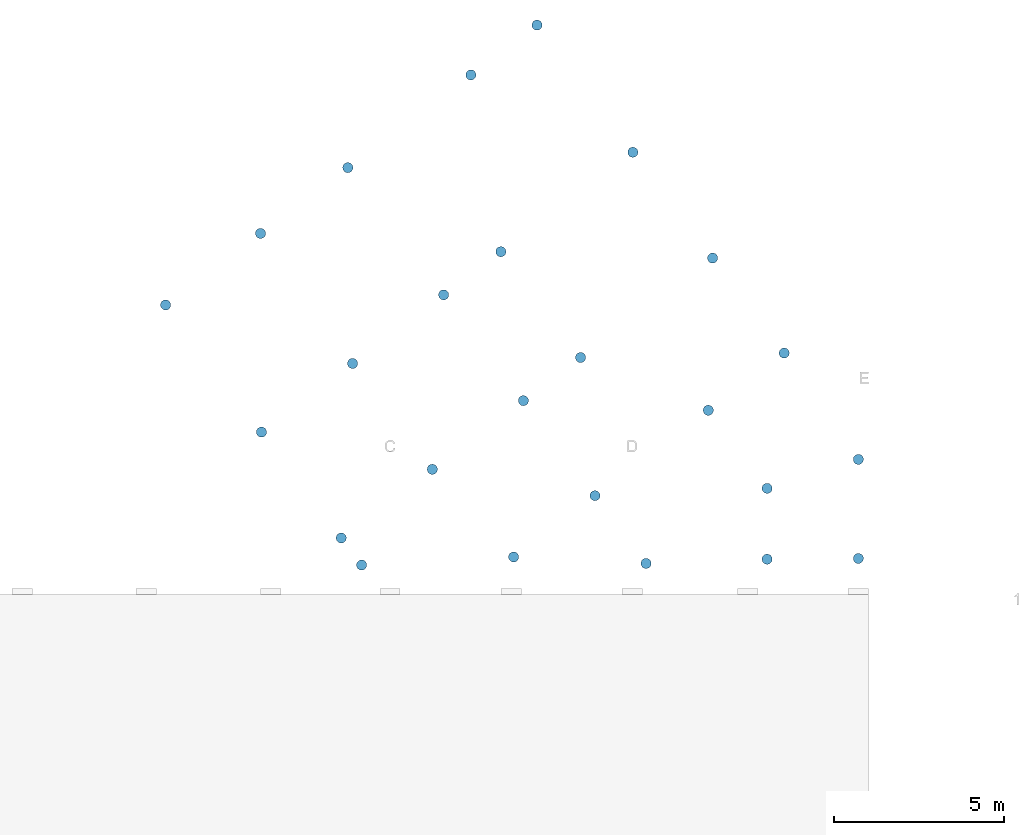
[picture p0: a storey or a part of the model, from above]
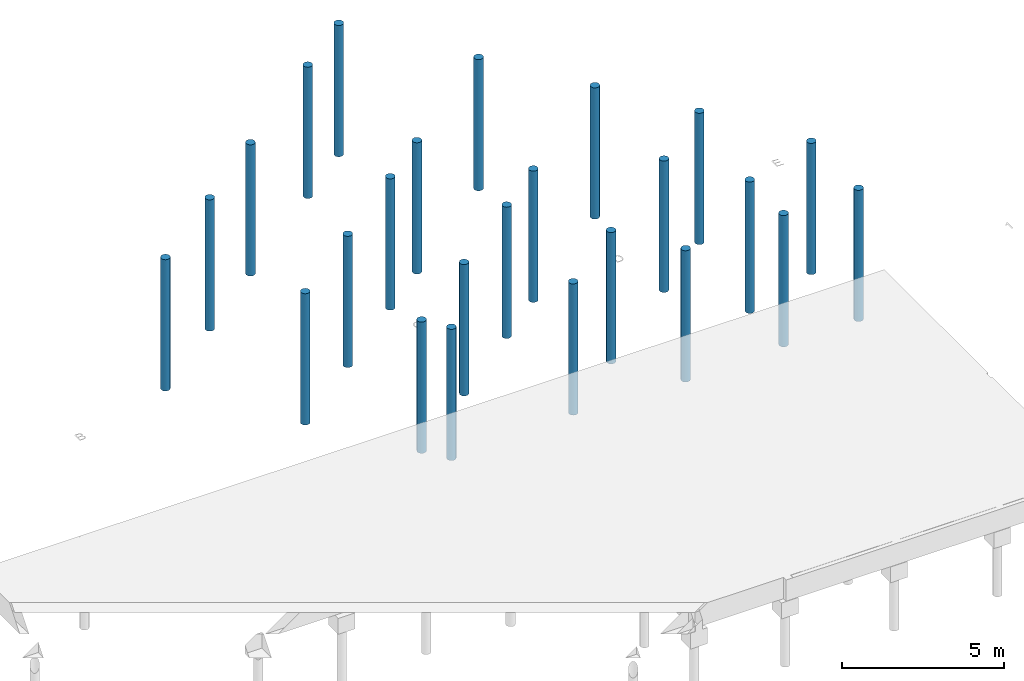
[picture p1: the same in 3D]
Properties of the parts of a building model (IFC2X3)

# File
Description: ViewDefinition [CoordinationView_V2.0], Option [Drawing Scale: 100.000000], Option [Global Unique Identifiers (GUID): Keep existing], Option [Elements to export: Entire project], Option [Partial Structure Display: Entire Model], Option [IFC Domain: All], Option [Structural Function: All Elements], Option [Convert Grid elements: On], Option [Convert IFC Annotations and ArchiCAD 2D elements: On], Option [Convert 2D symbols of Doors and Windows: Off], Option [Explode Composite and Complex Profile elements into parts: Off], Option [Export geometries that Participates in Collision Detection only: Off], Option [Multi-skin complex geometries: Building element parts], Option [Elements in Solid Element Operations: Extruded/revolved], Option [Elements with junctions: Extruded/revolved without junctions], Option [Slabs with slanted edge(s): Extruded], Option [Use legacy geometric methods as in Coordination View 1.0: Off], Option [IFC Site Geometry: As boundary representation (BRep)], Option [Properties To Export: All properties], Option [Space containment: Off], Option [Bounding Box: Off], Option [Geometry to type objects: Off], Option [IFC base quantities (size, area and volume): Off], Option [All ArchiCAD BIM parameters: On], Option [IFC Space boundaries: Off], Option [ArchiCAD Zone Categories as IFC Space classification data: Off]
File name: J:\STATION DOCUMENTS\TB2E COMMI\SESSION 2016\Agonac PLN\test IFC\maquette01.ifc
Time: 2016-01-28T13:49:23
Author: Architect
Organization: Building Designer Office
Written by: PreProc - EDM 5.0
Made in: IFC file generated by Graphisoft ArchiCAD-64 19.0.0 FRA FULL Windows version (IFC2x3 add-on version: 3003 FRA FULL).
Authorization: The authorising person

# IfcProject, Default Project
Description: Description of Default Project

# IfcSite, Default Site
Description: Description of Default Site; RefLatitude: 24, 28, 0, 0; RefLongitude: 54, 25, 0, 0; RefElevation: 10 mm

# IfcBuilding, Default Building
Description: Description of Default Building

# IfcBuildingStorey (4)
In: Default Building
Name | Elevation (mm)
FONDATIONS PROFONDES | -3600
FONDATIONS SUPERFICIELLES | -1600
RDC MAIRE | 0
REZ JARDIN LOISIRS | 3950

# IfcBeam: Longrine becquet 200 x 800 (18)
In: FONDATIONS SUPERFICIELLES
Material: Struct. - B.A. coulé
BE BETON - Enrobage: 3 cm; Type béton: XC1; Ratio Acier: 150 kg/m3; Classe béton: C25/30
ArchiCADProperties - Etage d'implantation: FONDATIONS SUPERFICIELLES; Calque: Longrine becquet 20x80 ht; Type: Poutre; Verrouillé: no; Matériau de construction / Composite / Profil / Hachure: Longrine becquet; Fonction structurelle: Elément porteur; Position: Extérieur; Classification d'élement: Poutre; Etat de rénovation: Existant; Afficher sur filtre de rénovation: Tous les filtres appropriés; Type de structure: Profil complexe; Matériau de construction / Profil: Longrine becquet; Angle d'inclinaison de poutre: 0 deg; Coupe transversale de poutre: Profilé
AC_Pset_RenovationAndPhasing - Renovation Status: Existing
Pset_BeamCommon - LoadBearing: yes; IsExternal: yes; Reference: Longrine becquet 200 x 800
ArchiCADQuantities - Altitude à Zéro du Projet: 2950 mm; Altitude à étage: 4550 mm; Hauteur: 800 mm; Surface de fin: 0.245 m2; Surface des trous: 0 m2; Surface des arêtes de trou: 0 m2; Nombre de trous: 0; Volume des trous: 0 m3; Largeur des trous: 0 mm; Hauteur du trou: 0 mm; Niveau du trou: 0 mm; Largeur: 200 mm; Décalage: 0 mm
Name | ID Elément entier = ID Elément compact | Superficie de surface (m2) | Volume net (m3) = Volume (m3) = Volume conditionnel (m3) | Superficie (m2) = Surface inférieure (m2) = Surface supérieure (m2) | Longueur droite (mm) = Longueur gauche (mm) | Surface côté gauche (m2) = Surface côté droit (m2)
LONGRINE_B_20x80-015 | LONGRINE_B_20x80-015 | 1.82354 | 0.0966857 | 0.157854 | 789.271 | 0.631417
LONGRINE_B_20x80-014 | LONGRINE_B_20x80-014 | 5.28219 | 0.308528 | 0.503719 | 2518.6 | 2.01488
LONGRINE_B_20x80-012 | LONGRINE_B_20x80-012 | 5.87681 | 0.344949 | 0.563181 | 2815.91 | 2.25273
LONGRINE_B_20x80-013 | LONGRINE_B_20x80-013 | 10.871 | 0.650843 | 1.0626 | 5313 | 4.2504
LONGRINE_B_20x80-016 | LONGRINE_B_20x80-016 | 1.845 | 0.098 | 0.16 | 800 | 0.64
LONGRINE_B_20x80-011 | LONGRINE_B_20x80-011 | 5.62033 | 0.329239 | 0.537533 | 2687.67 | 2.15013
LONGRINE_B_20x80-009 | LONGRINE_B_20x80-009 | 5.645 | 0.33075 | 0.54 | 2700 | 2.16
LONGRINE_B_20x80-010 | LONGRINE_B_20x80-010 | 1.73299 | 0.0911397 | 0.148799 | 743.997 | 0.595198
LONGRINE_B_20x80-008 | LONGRINE_B_20x80-008 | 7.61995 | 0.451716 | 0.737495 | 3687.48 | 2.94998
LONGRINE_B_20x80-007 | LONGRINE_B_20x80-007 | 6.855 | 0.404862 | 0.661 | 3305 | 2.644
LONGRINE_B_20x80-006 | LONGRINE_B_20x80-006 | 7.653 | 0.45374 | 0.7408 | 3704 | 2.9632
LONGRINE_B_20x80-005 | LONGRINE_B_20x80-005 | 9.227 | 0.550147 | 0.8982 | 4491 | 3.5928
LONGRINE_B_20x80-004 | LONGRINE_B_20x80-004 | 4.725 | 0.2744 | 0.448 | 2240 | 1.792
LONGRINE_B_20x80-003 | LONGRINE_B_20x80-003 | 8.925 | 0.53165 | 0.868 | 4340 | 3.472
LONGRINE_B_20x80-002 | LONGRINE_B_20x80-002 | 6.285 | 0.36995 | 0.604 | 3020 | 2.416
LONGRINE_B_20x80-017 | LONGRINE_B_20x80-017 | 7.653 | 0.45374 | 0.7408 | 3704 | 2.9632
LONGRINE_B_20x80-018 | LONGRINE_B_20x80-018 | 9.227 | 0.550147 | 0.8982 | 4491 | 3.5928
LONGRINE_B_20x80-001 | LONGRINE_B_20x80-001 | 6.845 | 0.40425 | 0.66 | 3300 | 2.64

# IfcBeam: Struct. - B.A. coulé 200 x 550 (20)
In: FONDATIONS SUPERFICIELLES
Material: Struct. - B.A. coulé
BE BETON - Enrobage: 3 cm; Type béton: XC1; Ratio Acier: 150 kg/m3
ArchiCADProperties - Etage d'implantation: FONDATIONS SUPERFICIELLES; Calque: Longrine 20x55 ht; Type: Poutre; Verrouillé: yes; Matériau de construction / Composite / Profil / Hachure: Struct. - B.A. coulé; Fonction structurelle: Elément porteur; Position: Extérieur; Classification d'élement: Poutre; Etat de rénovation: Existant; Afficher sur filtre de rénovation: Tous les filtres appropriés; Type de structure: Basique; Surface supérieure: Béton - Brut de décoffrage (Planches); Surface inférieure: Béton - Brut de décoffrage (Planches); Surface gauche: Béton - Brut de décoffrage (Planches); Surface droite: Béton - Brut de décoffrage (Planches); Surface de fin: Béton - Brut de décoffrage (Planches); Matériau de construction / Profil: Struct. - B.A. coulé; Angle d'inclinaison de poutre: 0 deg; Coupe transversale de poutre: Rectangulaire
AC_Pset_RenovationAndPhasing - Renovation Status: Existing
Pset_BeamCommon - LoadBearing: yes; IsExternal: yes; Reference: Struct. - B.A. coulé 200 x 550
ArchiCADQuantities - Altitude à Zéro du Projet: 3500 mm; Altitude à étage: 5100 mm; Hauteur: 550 mm; Surface de fin: 0.22 m2; Surface des trous: 0 m2; Surface des arêtes de trou: 0 m2; Nombre de trous: 0; Volume des trous: 0 m3; Largeur des trous: 0 mm; Hauteur du trou: 0 mm; Niveau du trou: 0 mm; Largeur: 200 mm; Décalage: 0 mm
Name | Classe béton | ID Elément entier = ID Elément compact | Superficie de surface (m2) | Volume net (m3) = Volume (m3) = Volume conditionnel (m3) | Superficie (m2) = Surface inférieure (m2) = Surface supérieure (m2) | Longueur droite (mm) = Longueur gauche (mm) | Surface côté gauche (m2) = Surface côté droit (m2)
LONGRINE_20x55-020 | C25/30 | LONGRINE_20x55-020 | 1.30318 | 0.079433 | 0.144424 | 722.118 | 0.397165
LONGRINE_20x55-019 | C25/30 | LONGRINE_20x55-019 | 3.15156 | 0.214981 | 0.390875 | 1954.37 | 1.07491
LONGRINE_20x55-017 | C25/30 | LONGRINE_20x55-017 | 4.2385 | 0.29469 | 0.5358 | 2679 | 1.47345
LONGRINE_20x55-015 | C25/30 | LONGRINE_20x55-015 | 4.12 | 0.286 | 0.52 | 2600 | 1.43
LONGRINE_20x55-014 | C25/30 | LONGRINE_20x55-014 | 6.19 | 0.4378 | 0.796 | 3980 | 2.189
LONGRINE_20x55-012 | C25/30 | LONGRINE_20x55-012 | 2.08473 | 0.136747 | 0.24863 | 1243.15 | 0.683733
LONGRINE_20x55-013 | C25/30 | LONGRINE_20x55-013 | 4.42 | 0.308 | 0.56 | 2800 | 1.54
LONGRINE_20x55-018 | C25/30 | LONGRINE_20x55-018 | 1.26617 | 0.0767188 | 0.139489 | 697.443 | 0.383594
LONGRINE_20x55-016 | C25/30 | LONGRINE_20x55-016 | 3.67 | 0.253 | 0.46 | 2300 | 1.265
LONGRINE-011 |  | LONGRINE-011 | 5.1775 | 0.36355 | 0.661 | 3305 | 1.81775
LONGRINE_20x55-006 | C25/30 | LONGRINE_20x55-006 | 5.776 | 0.40744 | 0.7408 | 3704 | 2.0372
LONGRINE_20x55-010 | C25/30 | LONGRINE_20x55-010 | 7.22734 | 0.513872 | 0.934312 | 4671.56 | 2.56936
LONGRINE_20x55-009 | C25/30 | LONGRINE_20x55-009 | 3.08266 | 0.209928 | 0.381688 | 1908.44 | 1.04964
LONGRINE_20x55-008 | C25/30 | LONGRINE_20x55-008 | 4.96 | 0.3476 | 0.632 | 3160 | 1.738
LONGRINE_20x55-007 | C25/30 | LONGRINE_20x55-007 | 4.96 | 0.3476 | 0.632 | 3160 | 1.738
LONGRINE_20x55-005 | C25/30 | LONGRINE_20x55-005 | 7.22734 | 0.513872 | 0.934312 | 4671.56 | 2.56936
LONGRINE_20x55-004 | C25/30 | LONGRINE_20x55-004 | 3.0865 | 0.21021 | 0.3822 | 1911 | 1.05105
LONGRINE_20x55-003 | C25/30 | LONGRINE_20x55-003 | 4.96 | 0.3476 | 0.632 | 3160 | 1.738
LONGRINE_20x55-002 | C25/30 | LONGRINE_20x55-002 | 4.96 | 0.3476 | 0.632 | 3160 | 1.738
LONGRINE_20x55-001 | C25/30 | LONGRINE_20x55-001 | 6.9565 | 0.49401 | 0.8982 | 4491 | 2.47005

# IfcFooting, Fondations mairie
In: FONDATIONS PROFONDES
Material: Sans Trame
ArchiCADProperties - ID Elément entier: Fondations mairie; ID Elément compact: Fondations mairie; Etage d'implantation: FONDATIONS PROFONDES; Calque: Fondations Mairie; Type: Objet; Verrouillé: no; Nom Elément de Bibliothèque: mairie; Matériau de construction / Composite / Profil / Hachure: Sans Trame; Fonction structurelle: Elément porteur; Position: Extérieur; Classification d'élement: Empattement; Etat de rénovation: Existant; Afficher sur filtre de rénovation: Tous les filtres appropriés; Angle de rotation: 0 deg; Surface: Peinture - Noir
AC_Pset_mairie - Afficher points chauds 2D en 3D: yes; Utiliser environnement mémorisé: no; Hachure 1: Béton armé; Hachure 2: Sans Trame; Hachure 3: Hachure solide; Ligne 1: 1; Ligne 2: 21; Ligne 3: 6; Ligne 4: 7; Surface 1: Béton - Brut de décoffrage (Planches); Surface 2: Peinture - Noir; Surface 3: Béton - Lissé; Surface 4: 0; Surface 5: Béton - Brut; Surface 6: Métal - Zinc; Surface 7: Peinture - Vermilion; Stylo 1: Fond - Couleur 1; Stylo 2: Général - Dessin; Stylo 3: Général - fonds de hachures; Stylo 4: Béton armé; Stylo 5: Poteaux - Contours; Stylo 6: Poteaux - fonds de hachure; Stylo 7: Poteaux - Hachures coupées; Stylo 8: Poteaux - Coupé structurel; Stylo 9: Objets - Général; Stylo 10: Eléments 2D - Général; Stylo 11: Système d'axe
AC_Pset_RenovationAndPhasing - Renovation Status: Existing
ArchiCADQuantities - Altitude à Zéro du Projet: -3600 mm; Altitude à étage: -4.44089e-13 mm; Superficie de surface: 1274.78 m2; Volume net: 126.644 m3; Superficie: 905.232 m2; Hauteur (Taille en Z): 3600 mm; Longueur (A): 40115 mm; Volume: 126.644 m3; Largeur (B): 22565.9 mm
AC_Equantity_mairie - 1ère dimension: 40115 mm; 2ème dimension: 22565.9 mm; Hauteur: 3600 mm; Niveau inférieur: 1000 mm; Niveau supérieur: 0 mm

# IfcFooting: Massifs (25)
In: FONDATIONS SUPERFICIELLES
Material: Struct. - B.A. coulé
BE BETON - Type de béton: XC1; Enrobage aciers: 3 cm; Ratio Acier: 80 kg/m3; Classe béton: C25/30
ArchiCADProperties - Etage d'implantation: FONDATIONS SUPERFICIELLES; Calque: Massifs loisir; Type: Poteau; Verrouillé: no; Matériau de construction / Composite / Profil / Hachure: Struct. - B.A. coulé; Fonction structurelle: Elément porteur; Position: Non défini; Classification d'élement: Empattement; Etat de rénovation: Existant; Afficher sur filtre de rénovation: Tous les filtres appropriés; Type de structure: Basique; Matériau de construction / Profil: Struct. - B.A. coulé; Surface: Béton - Brut de décoffrage (Planches); Angle d'inclinaison de poteau: 90 deg; Coupe transversale de poteau: Rectangulaire; Etage supérieur lié: Non lié
AC_Pset_RenovationAndPhasing - Renovation Status: Existing
ArchiCADQuantities - Altitude à Zéro du Projet: 2350 mm; Altitude à étage: 3950 mm; Hauteur: 600 mm; Superficie de surface: 1.44 m2; Volume net: 0.216 m3; Superficie: 0.36 m2; Surface nette de l'âme (sans haut/bas): 1.44 m2; Surface du revêtement: 0 m2; Volume net de l'Ame: 0.216 m3; Volume net du revêtement: 0 m3; Dimensions Ame: 600 mm; 2ème dimension âme: 600 mm; Hauteur minimum du Poteau: 600 mm; Hauteur maximum Poteau: 600 mm; Périmètre du Poteau: 2400 mm; Surface du Poteau: 0.36 m2; Volume du Poteau: 0.216 m3; Volume brut du Poteau: 0.216 m3; Surface brute de l'âme (sans haut/bas): 1.44 m2; Volume brut de l'Ame: 0.216 m3; Surface brute du revêtement (sans haut/bas): 0 m2; Volume brut du revêtement: 0 m3; Surface nette du haut de l'Ame: 0.36 m2; Surface nette du bas de l'Ame: 0.36 m2; Surface nette du haut du Revêtement: 0 m2; Surface nette du bas du Revêtement: 0 m2; Surface brute du haut (ou bas) de l'âme: 0.36 m2; Surface brute du haut (ou bas) du revêtement: 0 m2; Décalage étage d'implantation: 3950 mm; Décalage supérieur: -300 mm
Name | ID Elément entier = ID Elément compact
Plot-051 | Plot-051
Plot-060 | Plot-060
Plot-038 | Plot-038
Plot-036 | Plot-036
Plot-041 | Plot-041
Plot-039 | Plot-039
Plot-053 | Plot-053
Plot-050 | Plot-050
Plot-055 | Plot-055
Plot-056 | Plot-056
Plot-054 | Plot-054
Plot-059 | Plot-059
Plot-052 | Plot-052
Plot-057 | Plot-057
Plot-058 | Plot-058
Plot-043 | Plot-043
Plot-045 | Plot-045
Plot-037 | Plot-037
Plot-042 | Plot-042
Plot-044 | Plot-044
Plot-047 | Plot-047
Plot-048 | Plot-048
Plot-049 | Plot-049
Plot-046 | Plot-046
Plot-040 | Plot-040

# IfcPile (25)
In: FONDATIONS PROFONDES
Material: Struct. - B.A. coulé
ArchiCADProperties - Etage d'implantation: FONDATIONS PROFONDES; Calque: Pieu loisir; Type: Poteau; Verrouillé: no; Matériau de construction / Composite / Profil / Hachure: Struct. - B.A. coulé; Fonction structurelle: Elément porteur; Position: Extérieur; Classification d'élement: Pieu; Etat de rénovation: Existant; Afficher sur filtre de rénovation: Tous les filtres appropriés; Type de structure: Basique; Matériau de construction / Profil: Struct. - B.A. coulé; Surface: Béton - Brut de décoffrage (Planches); Angle d'inclinaison de poteau: 90 deg; Coupe transversale de poteau: Circulaire; Etage supérieur lié: Propre étage + 1 (1. FONDATIONS SUPERFICIELLES)
AC_Pset_RenovationAndPhasing - Renovation Status: Existing
ArchiCADQuantities - Altitude à Zéro du Projet: -2600 mm; Altitude à étage: 1000 mm; Hauteur: 4950 mm; Superficie de surface: 4.65548 m2; Volume net: 0.346966 m3; Superficie: 0.0706858 m2; Surface nette de l'âme (sans haut/bas): 4.65548 m2; Surface du revêtement: 0 m2; Volume net de l'Ame: 0.346966 m3; Volume net du revêtement: 0 m3; Dimensions Ame: 300 mm; 2ème dimension âme: 300 mm; Hauteur minimum du Poteau: 4950 mm; Hauteur maximum Poteau: 4950 mm; Périmètre du Poteau: 942.478 mm; Surface du Poteau: 0.0706858 m2; Volume du Poteau: 0.346966 m3; Volume brut du Poteau: 0.346966 m3; Surface brute de l'âme (sans haut/bas): 4.65548 m2; Volume brut de l'Ame: 0.346966 m3; Surface brute du revêtement (sans haut/bas): 0 m2; Volume brut du revêtement: 0 m3; Surface nette du haut de l'Ame: 0.0700941 m2; Surface nette du bas de l'Ame: 0.0700941 m2; Surface nette du haut du Revêtement: 0 m2; Surface nette du bas du Revêtement: 0 m2; Surface brute du haut (ou bas) de l'âme: 0.0706858 m2; Surface brute du haut (ou bas) du revêtement: 0 m2; Décalage étage d'implantation: 1000 mm; Décalage supérieur: 3950 mm
Name | ID Elément entier = ID Elément compact
Pieu-005 | Pieu-005
Pieu-004 | Pieu-004
Pieu-003 | Pieu-003
Pieu-002 | Pieu-002
Pieu001 | Pieu001
Pieu-006 | Pieu-006
Pieu-007 | Pieu-007
Pieu-008 | Pieu-008
Pieu-009 | Pieu-009
Pieu-010 | Pieu-010
Pieu-015 | Pieu-015
Pieu-014 | Pieu-014
Pieu-013 | Pieu-013
Pieu-012 | Pieu-012
Pieu-011 | Pieu-011
Pieu-016 | Pieu-016
Pieu-020 | Pieu-020
Pieu-019 | Pieu-019
Pieu-022 | Pieu-022
Pieu-023 | Pieu-023
Pieu-025 | Pieu-025
Pieu-024 | Pieu-024
Pieu-021 | Pieu-021
Pieu-018 | Pieu-018
Pieu-017 | Pieu-017

# IfcSlab: Struct. - B.A. coulé (30)
In: FONDATIONS SUPERFICIELLES
PredefinedType: FLOOR; Material: Struct. - B.A. coulé
ArchiCADProperties - Etage d'implantation: FONDATIONS SUPERFICIELLES; Calque: Clavetage; Type: Forme; Verrouillé: no; Matériau de construction / Composite / Profil / Hachure: Struct. - B.A. coulé; Fonction structurelle: Elément porteur; Classification d'élement: Dalle; Etat de rénovation: Existant; Afficher sur filtre de rénovation: Tous les filtres appropriés; Hachure: Struct. - B.A. coulé; Surface: Béton - Brut de décoffrage (Planches); Ombres portées: yes; Recevoir ombre: yes; Classification par DIN: Non défini
AC_Pset_RenovationAndPhasing - Renovation Status: Existing
Pset_SlabCommon - LoadBearing: yes
ArchiCADQuantities - Altitude à Zéro du Projet: 2950 mm; Altitude à étage: 4550 mm
Name | ID Elément entier = ID Elément compact | Position | Superficie de surface (m2) | Volume net (m3) = Volume (m3) | Superficie (m2) | Périmètre (mm) | IsExternal
Clav-024 | Clav-024 | Non défini | 0.420189 | 0.0146805 | 0.0266919 | 666.919
Clav-020 | Clav-020 | Extérieur | 0.52 | 0.022 | 0.04 | 800 | yes
Clav-021 | Clav-021 | Extérieur | 0.52 | 0.022 | 0.04 | 800 | yes
Clav-012 | Clav-012 | Extérieur | 0.52 | 0.022 | 0.04 | 800 | yes
Clav-013 | Clav-013 | Extérieur | 0.52 | 0.022 | 0.04 | 800 | yes
Clav-014 | Clav-014 | Extérieur | 0.52 | 0.022 | 0.04 | 800 | yes
Clav-009 | Clav-009 | Extérieur | 0.52 | 0.022 | 0.04 | 800 | yes
Clav-022 | Clav-022 | Extérieur | 0.52 | 0.022 | 0.04 | 800 | yes
Clav-015 | Clav-015 | Extérieur | 0.52 | 0.022 | 0.04 | 800 | yes
Clav-005 | Clav-005 | Extérieur | 0.52 | 0.022 | 0.04 | 800 | yes
Clav-004 | Clav-004 | Extérieur | 0.52 | 0.022 | 0.04 | 800 | yes
Clav-003 | Clav-003 | Extérieur | 0.52 | 0.022 | 0.04 | 800 | yes
Clav-002 | Clav-002 | Extérieur | 0.52 | 0.022 | 0.04 | 800 | yes
Clav-010 | Clav-010 | Extérieur | 0.52 | 0.022 | 0.04 | 800 | yes
Clav-008 | Clav-008 | Extérieur | 0.52 | 0.022 | 0.04 | 800 | yes
Clav-007 | Clav-007 | Extérieur | 0.52 | 0.022 | 0.04 | 800 | yes
Clav-016 | Clav-016 | Extérieur | 0.52 | 0.022 | 0.04 | 800 | yes
Clav-011 | Clav-011 | Extérieur | 0.52 | 0.022 | 0.04 | 800 | yes
Clav-006 | Clav-006 | Extérieur | 0.52 | 0.022 | 0.04 | 800 | yes
Clav-001 | Clav-001 | Extérieur | 0.52 | 0.022 | 0.04 | 800 | yes
Clav-030 | Clav-030 | Non défini | 0.52 | 0.022 | 0.04 | 800
Clav-026 | Clav-026 | Non défini | 0.680939 | 0.0358361 | 0.0651565 | 1001.14
Clav-028 | Clav-028 | Non défini | 0.499708 | 0.0205116 | 0.0372938 | 772.946
Clav-018 | Clav-018 | Non défini | 0.844768 | 0.0511536 | 0.0930065 | 1197.74
Clav-023 | Clav-023 | Non défini | 0.52 | 0.022 | 0.04 | 800
Clav-025 | Clav-025 | Non défini | 0.618848 | 0.0292489 | 0.0531798 | 931.798
Clav-017 | Clav-017 | Non défini | 0.369574 | 0.0109688 | 0.0199433 | 599.433
Clav-027 | Clav-027 | Non défini | 0.52 | 0.022 | 0.04 | 800
Clav-019 | Clav-019 | Non défini | 0.52 | 0.022 | 0.04 | 800
Clav-029 | Clav-029 | Non défini | 0.52 | 0.022 | 0.04 | 800

# IfcSlab: Struct. - B.A. coulé 250, Dalle-LOISIR
In: REZ JARDIN LOISIRS
Material: Struct. - B.A. coulé 250 mm
ArchiCADProperties - ID Elément entier: Dalle-LOISIR; ID Elément compact: Dalle-LOISIR; Etage d'implantation: REZ JARDIN LOISIRS; Calque: Dalles centre loisir; Type: Dalle; Verrouillé: no; Matériau de construction / Composite / Profil / Hachure: Struct. - B.A. coulé; Fonction structurelle: Elément porteur; Position: Intérieur; Classification d'élement: Dalle; Etat de rénovation: Existant; Afficher sur filtre de rénovation: Tous les filtres appropriés; Type de structure: Basique; Surface supérieure: Béton - Brut de décoffrage (Planches); Surface latérale: Béton - Brut de décoffrage (Planches); Surface inférieure: Béton - Brut de décoffrage (Planches); Matériau de construction / Composite: Struct. - B.A. coulé; Hachure de recouvrement: 25 %; Emplacement de plan de référence: Haut
AC_Pset_RenovationAndPhasing - Renovation Status: Existing
Pset_SlabCommon - LoadBearing: yes; IsExternal: no
ArchiCADQuantities - Altitude à Zéro du Projet: 3750 mm; Altitude à étage: -200 mm; Hauteur: 250 mm; Superficie de surface: 212.615 m2; Volume net: 53.1538 m3; Superficie: 212.615 m2; Surface inférieure: 212.615 m2; Surface supérieure: 212.615 m2; Surface d'arête: 11.8662 m2; Volume: 53.1538 m3; Périmètre: 60950.8 mm; Surface des trous: 0 m2; Périmètre des trous: 0 mm; Epaisseur: 250 mm; Surface brute supérieure de la Dalle: 212.62 m2; Surface brute inférieure de la Dalle: 212.62 m2; Surface brute des bords de la Dalle: 15.2377 m2; Volume brut de la Dalle: 53.155 m3; Surface conditionnelle inférieure: 212.615 m2; Surface conditionnelle supérieure: 212.615 m2; Volume conditionnel: 53.1538 m3; Surface brute supérieure de la dalle avec trous: 212.62 m2; Surface brute inférieure de la dalle avec trous: 212.62 m2; Surface brute des arêtes de la dalle avec trous: 15.2377 m2; Volume brut de la dalle avec trous: 53.155 m3; Altitude supérieure: 3750 mm; Altitude inférieure: 3500 mm

# IfcWall: SUPERSTRUCTURE, Superstructure
In: RDC MAIRE
Material: Sans Trame
ArchiCADProperties - ID Elément entier: Superstructure; ID Elément compact: Superstructure; Etage d'implantation: RDC MAIRE; Calque: Superstructure; Type: Objet; Verrouillé: no; Nom Elément de Bibliothèque: SUPERSTRUCTURE; Matériau de construction / Composite / Profil / Hachure: Sans Trame; Fonction structurelle: Elément porteur; Position: Extérieur; Classification d'élement: Mur; Etat de rénovation: Existant; Afficher sur filtre de rénovation: Tous les filtres appropriés; Angle de rotation: 0 deg; Surface: Peinture - Noir
AC_Pset_SUPERSTRUCTURE - Afficher points chauds 2D en 3D: yes; Utiliser environnement mémorisé: no; Hachure 1: 0; Hachure 2: 100 %; Hachure 3: Pierre 01; Hachure 4: 0; Hachure 5: Hachure solide; Hachure 6: Béton armé; Hachure 7: Hachure solide*; Hachure 8: Sans Trame; Ligne 1: 1; Ligne 2: 21; Surface 1: 0; Surface 2: 0; Surface 3: 0; Surface 4: Brique - appareil courant; Surface 5: 0; Surface 6: 0; Surface 7: 0; Surface 8: 0; Surface 9: 0; Surface 10: 0; Surface 11: 0; Surface 12: 0; Surface 13: Béton - Brut de décoffrage (Planches); Surface 14: 0; Surface 15: 0; Surface 16: 0; Surface 17: 0; Surface 18: 0; Surface 19: 0; Surface 20: 0; Surface 21: 0; Surface 22: 0; Surface 23: 0; Surface 24: 0; Surface 25: 0; Surface 26: 0; Surface 27: 0; Surface 28: 0; Surface 29: 0; Stylo 1: Fond - Couleur 1; Stylo 2: Electrique - réseaux technologiques; Stylo 3: Herbe - Hachure; Stylo 4: Technique - Gaz; Stylo 5: Objets - Général; Stylo 6: Fond - Couleur 5; Stylo 7: Escaliers - Contours; Stylo 8: Structurel - Contours; Stylo 9: Général - Dessin; Stylo 10: Zone - Général; Stylo 11: Béton armé - Hachure; Stylo 12: Zone - Contours et hachures de recouvrement; Stylo 13: Maillage - Contours et hachures de recouvrement; Stylo 14: Général - Coupé non structurel; Stylo 15: Toit - Hachures coupées; Stylo 16: Général - fonds de hachures; Stylo 17: Béton armé; Stylo 18: A démolir - Hachures; Stylo 19: Poteaux - Général; Stylo 20: Hachure - Couleur 5; Stylo 21: Ouvertures - Non coupé/Au-dessus tête; Stylo 22: Ouvertures - Coupé structurel; Stylo 23: Ouvertures - Coupé non structurel; Stylo 24: Ouvertures - Général; Stylo 25: Ouvertures - Symboles et séparateurs; Stylo 26: Eléments 2D - Général; Stylo 27: Général - Symboles et séparateurs
AC_Pset_RenovationAndPhasing - Renovation Status: Existing
Pset_WallCommon - LoadBearing: yes; IsExternal: yes
ArchiCADQuantities - Altitude à Zéro du Projet: -400.02 mm; Altitude à étage: -400.02 mm; Superficie de surface: 3770.63 m2; Volume net: 354.69 m3; Superficie: 1108.57 m2; Hauteur (Taille en Z): 8250 mm; Longueur (A): 34744.2 mm; Volume: 354.69 m3; Largeur (B): 31906.7 mm
AC_Equantity_SUPERSTRUCTURE - 1ère dimension: 34744.2 mm; 2ème dimension: 31906.7 mm; Hauteur: 8250 mm; Niveau inférieur: 1000 mm; Niveau supérieur: 0 mm
